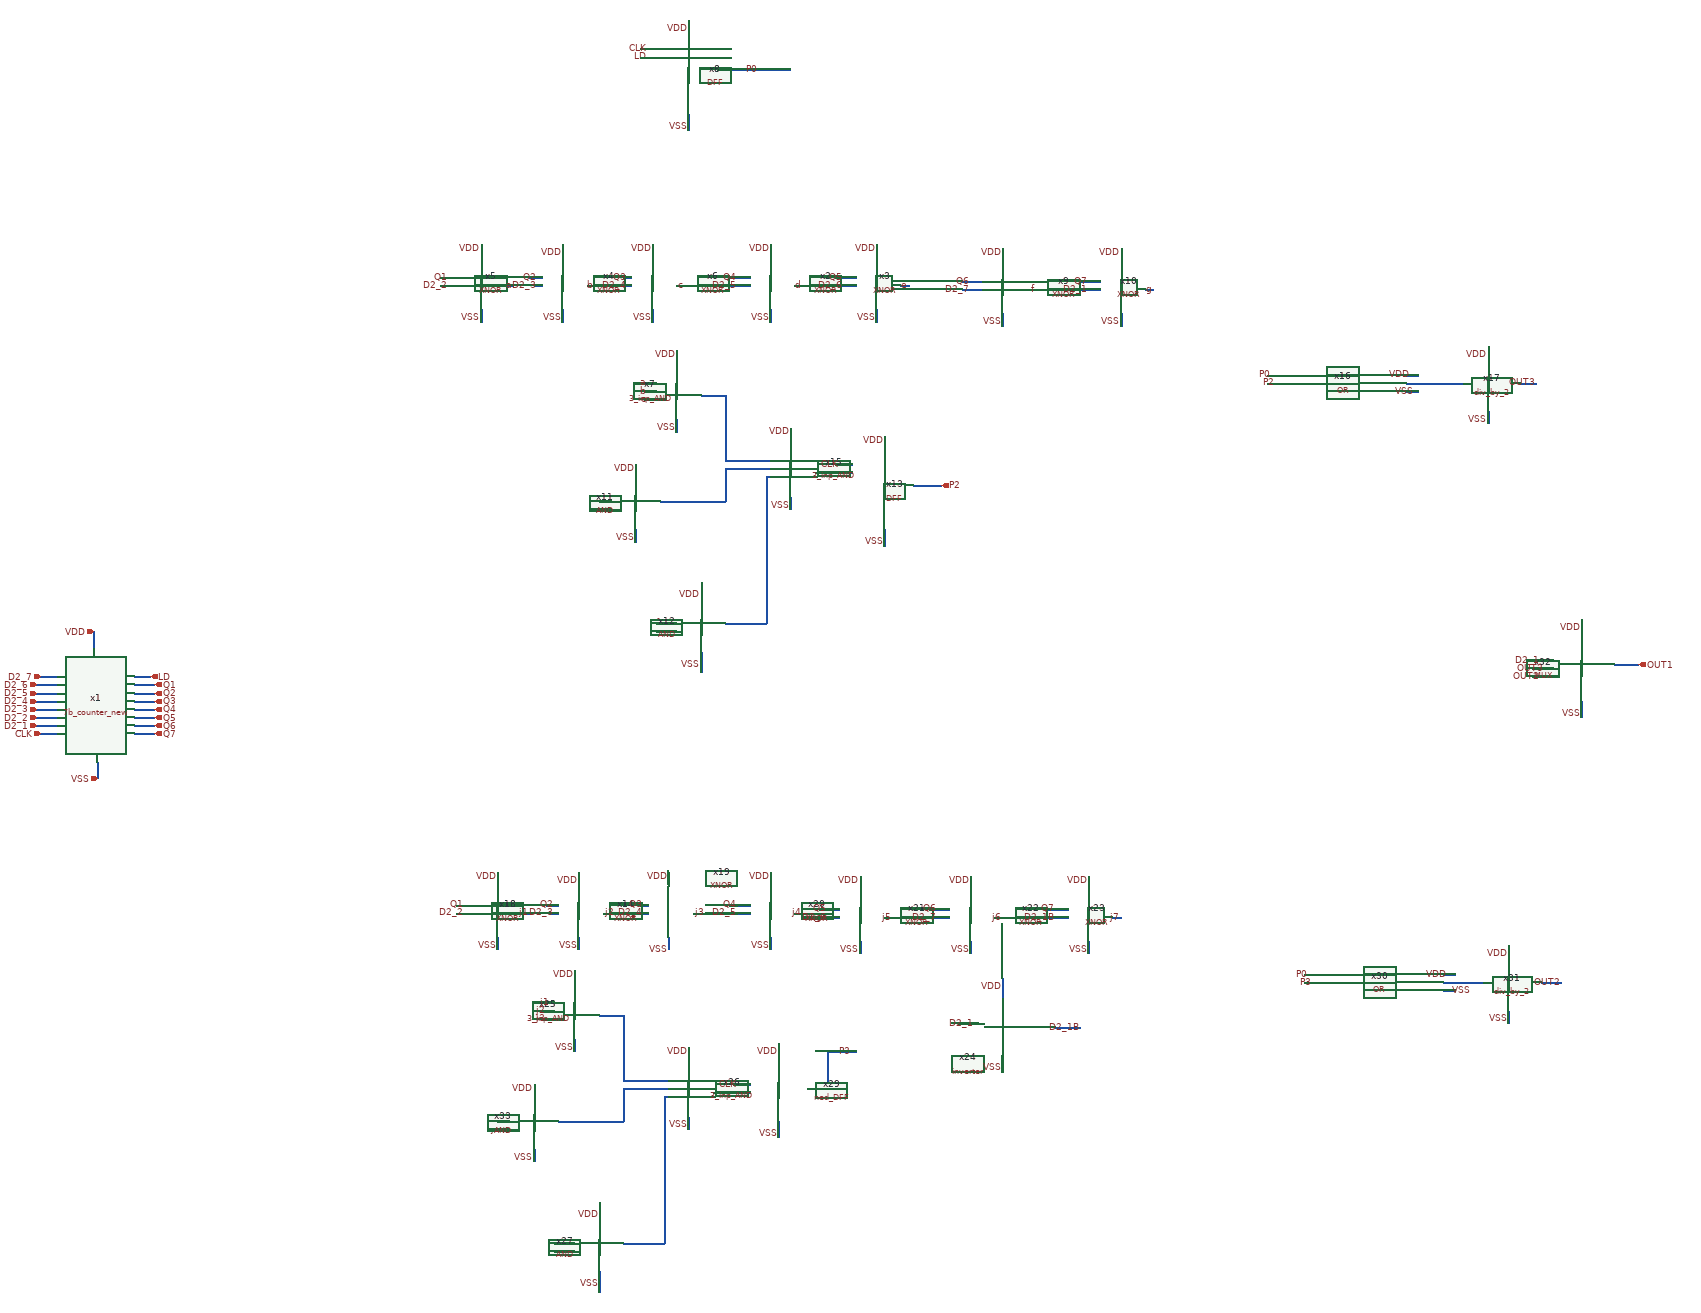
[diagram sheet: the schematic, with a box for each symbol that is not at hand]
v {xschem version=3.4.8RC file_version=1.3}
G {}
K {}
V {}
S {}
F {}
E {}
N 550 -1620 550 -1580 {
lab=VDD}
N 560 -1300 560 -1260 {
lab=VSS}
N 420 -1370 460 -1370 {
lab=CLK}
N 650 -1510 690 -1510 {
lab=LD}
N 410 -1390 460 -1390 {
lab=D2_1}
N 410 -1430 460 -1430 {
lab=D2_3}
N 410 -1410 460 -1410 {
lab=D2_2}
N 410 -1450 460 -1450 {
lab=D2_4}
N 410 -1470 460 -1470 {
lab=D2_5}
N 410 -1490 460 -1490 {
lab=D2_6}
N 420 -1510 460 -1510 {
lab=D2_7}
N 650 -1490 700 -1490 {
lab=Q1}
N 650 -1470 700 -1470 {
lab=Q2}
N 650 -1450 700 -1450 {
lab=Q3}
N 650 -1430 700 -1430 {
lab=Q4}
N 650 -1410 700 -1410 {
lab=Q5}
N 650 -1390 700 -1390 {
lab=Q6}
N 650 -1370 700 -1370 {
lab=Q7}
N 1400 -2490 1450 -2490 {
lab=Q1}
N 1400 -2470 1450 -2470 {
lab=D2_2}
N 1620 -2490 1650 -2490 {
lab=Q2}
N 1630 -2470 1650 -2470 {
lab=D2_3}
N 1850 -2490 1870 -2490 {
lab=Q3}
N 1850 -2470 1870 -2470 {
lab=D2_4}
N 1760 -2470 1790 -2470 {
lab=b}
N 1500 -2570 1500 -2540 {
lab=VDD}
N 1500 -2410 1500 -2380 {
lab=VSS}
N 1700 -2570 1700 -2540 {
lab=VDD}
N 1700 -2410 1700 -2380 {
lab=VSS}
N 1920 -2570 1920 -2540 {
lab=VDD}
N 1920 -2410 1920 -2380 {
lab=VSS}
N 1980 -2470 2010 -2470 {
lab=c}
N 1560 -2470 1580 -2470 {
lab=a}
N 1900 -2230 1930 -2230 {
lab=a}
N 1900 -2210 1930 -2210 {
lab=b}
N 1900 -2190 1930 -2190 {
lab=c}
N 1980 -2310 1980 -2280 {
lab=VDD}
N 2560 -1980 2630 -1980 {
lab=P2}
N 2110 -2490 2160 -2490 {
lab=Q4}
N 2110 -2470 2160 -2470 {
lab=D2_5}
N 2210 -2570 2210 -2540 {
lab=VDD}
N 2210 -2410 2210 -2380 {
lab=VSS}
N 2270 -2470 2290 -2470 {
lab=d}
N 2370 -2490 2420 -2490 {
lab=Q5}
N 2370 -2470 2420 -2470 {
lab=D2_6}
N 2470 -2570 2470 -2540 {
lab=VDD}
N 2470 -2410 2470 -2380 {
lab=VSS}
N 2530 -2470 2550 -2470 {
lab=e}
N 2680 -2480 2730 -2480 {
lab=Q6}
N 2680 -2460 2730 -2460 {
lab=D2_7}
N 2780 -2560 2780 -2530 {
lab=VDD}
N 2780 -2400 2780 -2370 {
lab=VSS}
N 2840 -2460 2860 -2460 {
lab=f}
N 2970 -2480 3020 -2480 {
lab=Q7}
N 2970 -2460 3020 -2460 {
lab=D2_1}
N 3070 -2560 3070 -2530 {
lab=VDD}
N 3070 -2400 3070 -2370 {
lab=VSS}
N 3130 -2460 3150 -2460 {
lab=g}
N 1980 -2140 1980 -2110 {
lab=VSS}
N 1790 -1940 1820 -1940 {
lab=d}
N 1790 -1920 1820 -1920 {
lab=e}
N 1880 -2030 1880 -2000 {
lab=VDD}
N 1880 -1870 1880 -1840 {
lab=VSS}
N 2040 -1740 2040 -1700 {
lab=VDD}
N 2040 -1570 2040 -1520 {
lab=VSS}
N 1930 -1640 1980 -1640 {
lab=f}
N 1930 -1620 1980 -1620 {
lab=g}
N 2180 -2040 2210 -2040 {
lab=#net1}
N 2180 -2020 2210 -2020 {
lab=#net2}
N 2260 -2120 2260 -2090 {
lab=VDD}
N 2260 -1950 2260 -1920 {
lab=VSS}
N 2040 -2200 2100 -2200 {
lab=#net1}
N 2100 -2200 2100 -2040 {
lab=#net1}
N 2100 -2040 2180 -2040 {
lab=#net1}
N 2030 -1940 2100 -1940 {
lab=#net2}
N 2100 -2020 2100 -1960 {
lab=#net2}
N 2100 -2020 2180 -2020 {
lab=#net2}
N 2200 -2000 2210 -2000 {
lab=#net3}
N 2320 -2010 2380 -2010 {
lab=#net4}
N 3430 -2250 3470 -2250 {
lab=P0}
N 3430 -2230 3470 -2230 {
lab=P2}
N 3770 -2250 3800 -2250 {
lab=VDD}
N 3770 -2210 3800 -2210 {
lab=VSS}
N 3860 -2230 3910 -2230 {
lab=#net5}
N 3970 -2320 3970 -2290 {
lab=VDD}
N 3970 -2160 3970 -2130 {
lab=VSS}
N 4050 -2230 4090 -2230 {
lab=OUT3}
N 2200 -2000 2200 -1660 {
lab=#net3}
N 1940 -1940 2030 -1940 {
lab=#net2}
N 2100 -1640 2200 -1640 {
lab=#net3}
N 2010 -3120 2010 -3080 {
lab=VDD}
N 2010 -2890 2010 -2850 {
lab=VSS}
N 1890 -3050 1930 -3050 {
lab=CLK}
N 1890 -3030 1930 -3030 {
lab=LD}
N 2080 -3000 2120 -3000 {
lab=P0}
N 2490 -2100 2490 -2060 {
lab=VDD}
N 2490 -1870 2490 -1830 {
lab=VSS}
N 2370 -2030 2410 -2030 {
lab=CLK}
N 2380 -2010 2410 -2010 {
lab=#net4}
N 1440 -950 1490 -950 {
lab=Q1}
N 1440 -930 1490 -930 {
lab=D2_2}
N 1660 -950 1690 -950 {
lab=Q2}
N 1670 -930 1690 -930 {
lab=D2_3}
N 1890 -950 1910 -950 {
lab=Q3}
N 1890 -930 1910 -930 {
lab=D2_4}
N 1800 -930 1830 -930 {
lab=j2}
N 1540 -1030 1540 -1000 {
lab=VDD}
N 1540 -870 1540 -840 {
lab=VSS}
N 1740 -1030 1740 -1000 {
lab=VDD}
N 1740 -870 1740 -840 {
lab=VSS}
N 1960 -1030 1960 -1000 {
lab=VDD}
N 1960 -870 1960 -840 {
lab=VSS}
N 2020 -930 2050 -930 {
lab=j3}
N 1600 -930 1620 -930 {
lab=j1}
N 2110 -950 2160 -950 {
lab=Q4}
N 2110 -930 2160 -930 {
lab=D2_5}
N 2210 -1030 2210 -1000 {
lab=VDD}
N 2210 -870 2210 -840 {
lab=VSS}
N 2270 -930 2290 -930 {
lab=j4}
N 2330 -940 2380 -940 {
lab=Q5}
N 2330 -920 2380 -920 {
lab=D2_6}
N 2430 -1020 2430 -990 {
lab=VDD}
N 2430 -860 2430 -830 {
lab=VSS}
N 2490 -920 2510 -920 {
lab=j5}
N 2600 -940 2650 -940 {
lab=Q6}
N 2600 -920 2650 -920 {
lab=D2_7}
N 2700 -1020 2700 -990 {
lab=VDD}
N 2700 -860 2700 -830 {
lab=VSS}
N 2760 -920 2780 -920 {
lab=j6}
N 2890 -940 2940 -940 {
lab=Q7}
N 2890 -920 2940 -920 {
lab=D2_1B}
N 2990 -1020 2990 -990 {
lab=VDD}
N 2990 -860 2990 -830 {
lab=VSS}
N 3050 -920 3070 -920 {
lab=j7}
N 2910 -650 2970 -650 {
lab=D2_1B}
N 2670 -660 2720 -660 {
lab=D2_1}
N 2780 -770 2780 -720 {
lab=VDD}
N 2780 -580 2780 -540 {
lab=VSS}
N 1650 -710 1680 -710 {
lab=j1}
N 1650 -690 1680 -690 {
lab=j2}
N 1650 -670 1680 -670 {
lab=j3}
N 1730 -790 1730 -760 {
lab=VDD}
N 2350 -590 2420 -590 {
lab=P3}
N 1730 -620 1730 -590 {
lab=VSS}
N 1540 -420 1570 -420 {
lab=j4}
N 1540 -400 1570 -400 {
lab=j5}
N 1630 -510 1630 -480 {
lab=VDD}
N 1630 -350 1630 -320 {
lab=VSS}
N 1790 -220 1790 -180 {
lab=VDD}
N 1790 -50 1790 0 {
lab=VSS}
N 1680 -120 1730 -120 {
lab=j6}
N 1680 -100 1730 -100 {
lab=j7}
N 1930 -520 1960 -520 {
lab=#net6}
N 1930 -500 1960 -500 {
lab=#net7}
N 2010 -600 2010 -570 {
lab=VDD}
N 2010 -430 2010 -400 {
lab=VSS}
N 1790 -680 1850 -680 {
lab=#net6}
N 1850 -680 1850 -520 {
lab=#net6}
N 1850 -520 1930 -520 {
lab=#net6}
N 1780 -420 1850 -420 {
lab=#net7}
N 1850 -500 1850 -440 {
lab=#net7}
N 1850 -500 1930 -500 {
lab=#net7}
N 1950 -480 1960 -480 {
lab=#net8}
N 2070 -490 2130 -490 {
lab=#net9}
N 1950 -480 1950 -140 {
lab=#net8}
N 1690 -420 1780 -420 {
lab=#net7}
N 1850 -120 1950 -120 {
lab=#net8}
N 2350 -570 2350 -510 {
lab=P3}
N 2230 -610 2230 -570 {
lab=VDD}
N 2230 -420 2230 -380 {
lab=VSS}
N 2120 -510 2160 -510 {
lab=CLK}
N 2300 -500 2340 -500 {
lab=P3}
N 2130 -490 2160 -490 {
lab=#net9}
N 2340 -500 2350 -500 {
lab=P3}
N 2350 -510 2350 -500 {
lab=P3}
N 2350 -590 2350 -570 {
lab=P3}
N 3520 -780 3560 -780 {
lab=P0}
N 3520 -760 3560 -760 {
lab=P3}
N 3860 -780 3890 -780 {
lab=VDD}
N 4020 -690 4020 -660 {
lab=VSS}
N 4100 -760 4150 -760 {
lab=OUT2}
N 4020 -850 4020 -820 {
lab=VDD}
N 3860 -740 3890 -740 {
lab=VSS}
N 3860 -760 3900 -760 {
lab=#net10}
N 4200 -1650 4200 -1610 {
lab=VDD}
N 4200 -1450 4200 -1410 {
lab=VSS}
N 4080 -1550 4130 -1550 {
lab=D2_1}
N 4080 -1530 4130 -1530 {
lab=OUT3}
N 4080 -1510 4130 -1510 {
lab=OUT2}
N 4280 -1540 4340 -1540 {
lab=OUT1}
N 2120 -3000 2170 -3000 {
lab=P0}
N 2220 -3000 2260 -3000 {
lab=P0}
N 2170 -3000 2220 -3000 {
lab=P0}
N 3900 -760 3960 -760 {
lab=#net10}
N 3770 -2230 3860 -2230 {
lab=#net5}
N 2100 -1960 2100 -1940 {lab=#net2}
N 2200 -1660 2200 -1640 {lab=#net3}
N 1850 -440 1850 -420 {lab=#net7}
N 1950 -140 1950 -120 {lab=#net8}
C {devices/iopin.sym} 550 -1620 3 0 {name=p1 lab=VDD}
C {devices/iopin.sym} 560 -1260 1 0 {name=p2 lab=VSS}
C {devices/ipin.sym} 410 -1390 0 0 {name=p3 lab=D2_1}
C {devices/ipin.sym} 420 -1370 0 0 {name=p4 lab=CLK}
C {devices/ipin.sym} 410 -1410 0 0 {name=p5 lab=D2_2}
C {devices/ipin.sym} 410 -1430 0 0 {name=p6 lab=D2_3}
C {devices/ipin.sym} 410 -1450 0 0 {name=p7 lab=D2_4}
C {devices/ipin.sym} 410 -1470 0 0 {name=p8 lab=D2_5}
C {devices/ipin.sym} 410 -1490 0 0 {name=p9 lab=D2_6}
C {devices/ipin.sym} 420 -1510 0 0 {name=p10 lab=D2_7}
C {devices/opin.sym} 690 -1510 0 0 {name=p12 lab=LD}
C {devices/opin.sym} 700 -1490 0 0 {name=p13 lab=Q1}
C {devices/opin.sym} 700 -1470 0 0 {name=p14 lab=Q2}
C {devices/opin.sym} 700 -1450 0 0 {name=p15 lab=Q3}
C {devices/opin.sym} 700 -1430 0 0 {name=p16 lab=Q4}
C {devices/opin.sym} 700 -1410 0 0 {name=p17 lab=Q5}
C {devices/opin.sym} 700 -1390 0 0 {name=p18 lab=Q6}
C {devices/opin.sym} 700 -1370 0 0 {name=p19 lab=Q7}
C {XNOR.sym} 1800 -2470 0 0 {name=x4}
C {XNOR.sym} 1600 -2470 0 0 {name=x5}
C {XNOR.sym} 2020 -2470 0 0 {name=x6}
C {devices/lab_wire.sym} 1500 -2560 0 0 {name=p21 sig_type=std_logic lab=VDD}
C {devices/lab_wire.sym} 1700 -2550 0 0 {name=p22 sig_type=std_logic lab=VDD}
C {devices/lab_wire.sym} 1920 -2560 0 0 {name=p23 sig_type=std_logic lab=VDD}
C {devices/lab_wire.sym} 1500 -2390 0 0 {name=p24 sig_type=std_logic lab=VSS}
C {devices/lab_wire.sym} 1700 -2390 0 0 {name=p25 sig_type=std_logic lab=VSS}
C {devices/lab_wire.sym} 1980 -2120 0 0 {name=p26 sig_type=std_logic lab=VSS}
C {devices/lab_wire.sym} 1420 -2490 0 0 {name=p27 sig_type=std_logic lab=Q1}
C {devices/lab_wire.sym} 1640 -2490 0 0 {name=p28 sig_type=std_logic lab=Q2}
C {devices/lab_wire.sym} 1860 -2490 0 0 {name=p29 sig_type=std_logic lab=Q3}
C {devices/lab_wire.sym} 1860 -2470 0 0 {name=p30 sig_type=std_logic lab=D2_4}
C {devices/lab_wire.sym} 1640 -2470 0 0 {name=p31 sig_type=std_logic lab=D2_3}
C {devices/lab_wire.sym} 1420 -2470 0 0 {name=p32 sig_type=std_logic lab=D2_2}
C {3_inp_AND.sym} 2080 -2210 0 0 {name=x7}
C {devices/lab_wire.sym} 1980 -2300 0 0 {name=p33 sig_type=std_logic lab=VDD}
C {devices/lab_wire.sym} 1580 -2470 0 0 {name=p35 sig_type=std_logic lab=a}
C {devices/lab_wire.sym} 1780 -2470 0 0 {name=p36 sig_type=std_logic lab=b}
C {devices/lab_wire.sym} 2000 -2470 0 0 {name=p37 sig_type=std_logic lab=c}
C {devices/lab_wire.sym} 1910 -2230 0 0 {name=p38 sig_type=std_logic lab=a}
C {devices/opin.sym} 2630 -1980 0 0 {name=p43 lab=P2}
C {XNOR.sym} 2310 -2470 0 0 {name=x2}
C {devices/lab_wire.sym} 2210 -2560 0 0 {name=p45 sig_type=std_logic lab=VDD}
C {devices/lab_wire.sym} 2210 -2390 0 0 {name=p46 sig_type=std_logic lab=VSS}
C {devices/lab_wire.sym} 2130 -2490 0 0 {name=p47 sig_type=std_logic lab=Q4}
C {devices/lab_wire.sym} 2130 -2470 0 0 {name=p48 sig_type=std_logic lab=D2_5}
C {devices/lab_wire.sym} 2290 -2470 0 0 {name=p49 sig_type=std_logic lab=d}
C {XNOR.sym} 2570 -2470 0 0 {name=x3}
C {devices/lab_wire.sym} 2470 -2560 0 0 {name=p50 sig_type=std_logic lab=VDD}
C {devices/lab_wire.sym} 2470 -2390 0 0 {name=p51 sig_type=std_logic lab=VSS}
C {devices/lab_wire.sym} 2390 -2490 0 0 {name=p52 sig_type=std_logic lab=Q5}
C {devices/lab_wire.sym} 2390 -2470 0 0 {name=p53 sig_type=std_logic lab=D2_6}
C {devices/lab_wire.sym} 2550 -2470 0 0 {name=p54 sig_type=std_logic lab=e}
C {XNOR.sym} 2880 -2460 0 0 {name=x9}
C {devices/lab_wire.sym} 2780 -2550 0 0 {name=p55 sig_type=std_logic lab=VDD}
C {devices/lab_wire.sym} 2780 -2380 0 0 {name=p56 sig_type=std_logic lab=VSS}
C {devices/lab_wire.sym} 2700 -2480 0 0 {name=p57 sig_type=std_logic lab=Q6}
C {devices/lab_wire.sym} 2700 -2460 0 0 {name=p58 sig_type=std_logic lab=D2_7}
C {devices/lab_wire.sym} 2860 -2460 0 0 {name=p59 sig_type=std_logic lab=f}
C {XNOR.sym} 3170 -2460 0 0 {name=x10}
C {devices/lab_wire.sym} 3070 -2550 0 0 {name=p60 sig_type=std_logic lab=VDD}
C {devices/lab_wire.sym} 3070 -2380 0 0 {name=p61 sig_type=std_logic lab=VSS}
C {devices/lab_wire.sym} 2990 -2480 0 0 {name=p62 sig_type=std_logic lab=Q7}
C {devices/lab_wire.sym} 3150 -2460 0 0 {name=p64 sig_type=std_logic lab=g}
C {devices/lab_wire.sym} 1880 -1850 0 0 {name=p34 sig_type=std_logic lab=VSS}
C {devices/lab_wire.sym} 1880 -2020 0 0 {name=p70 sig_type=std_logic lab=VDD}
C {devices/lab_wire.sym} 1800 -1940 0 0 {name=p71 sig_type=std_logic lab=d}
C {devices/lab_wire.sym} 1800 -1920 0 0 {name=p72 sig_type=std_logic lab=e}
C {devices/lab_wire.sym} 1940 -1640 0 0 {name=p75 sig_type=std_logic lab=f}
C {devices/lab_wire.sym} 2040 -1710 0 0 {name=p76 sig_type=std_logic lab=VDD}
C {devices/lab_wire.sym} 2040 -1540 0 0 {name=p77 sig_type=std_logic lab=VSS}
C {devices/lab_wire.sym} 2260 -1930 0 0 {name=p80 sig_type=std_logic lab=VSS}
C {3_inp_AND.sym} 2360 -2020 0 0 {name=x15}
C {devices/lab_wire.sym} 2260 -2110 0 0 {name=p81 sig_type=std_logic lab=VDD}
C {OR.sym} 3620 -2230 0 0 {name=x16}
C {devices/lab_wire.sym} 3780 -2250 1 0 {name=p84 sig_type=std_logic lab=VDD}
C {devices/lab_wire.sym} 3790 -2210 3 0 {name=p85 sig_type=std_logic lab=VSS}
C {div_by_2.sym} 4060 -2210 0 0 {name=x17}
C {devices/lab_wire.sym} 3970 -2300 0 0 {name=p86 sig_type=std_logic lab=VDD}
C {devices/lab_wire.sym} 3970 -2140 0 0 {name=p87 sig_type=std_logic lab=VSS}
C {devices/lab_wire.sym} 1910 -2210 0 0 {name=p94 sig_type=std_logic lab=b}
C {devices/lab_wire.sym} 1910 -2190 0 0 {name=p95 sig_type=std_logic lab=c}
C {devices/lab_wire.sym} 1940 -1620 0 0 {name=p39 sig_type=std_logic lab=g}
C {7b_counter_new.sym} 610 -1420 0 0 {name=x1}
C {devices/lab_wire.sym} 2990 -2460 0 0 {name=p11 sig_type=std_logic lab=D2_1}
C {devices/lab_wire.sym} 1910 -3030 0 0 {name=p20 sig_type=std_logic lab=LD}
C {DFF.sym} 2080 -3030 0 0 {name=x8}
C {devices/lab_wire.sym} 2010 -3100 0 0 {name=p40 sig_type=std_logic lab=VDD}
C {devices/lab_wire.sym} 2010 -2860 0 0 {name=p41 sig_type=std_logic lab=VSS}
C {devices/lab_wire.sym} 1910 -3050 0 0 {name=p42 sig_type=std_logic lab=CLK}
C {devices/lab_wire.sym} 3440 -2250 0 0 {name=p63 sig_type=std_logic lab=P0}
C {devices/lab_wire.sym} 2490 -2090 0 0 {name=p66 sig_type=std_logic lab=VDD}
C {devices/lab_wire.sym} 2490 -1840 0 0 {name=p67 sig_type=std_logic lab=VSS}
C {devices/lab_wire.sym} 2380 -2030 0 0 {name=p65 sig_type=std_logic lab=CLK}
C {XNOR.sym} 1840 -930 0 0 {name=x14}
C {XNOR.sym} 1640 -930 0 0 {name=x18}
C {XNOR.sym} 2060 -930 0 0 {name=x19}
C {devices/lab_wire.sym} 1540 -1020 0 0 {name=p68 sig_type=std_logic lab=VDD}
C {devices/lab_wire.sym} 1740 -1010 0 0 {name=p73 sig_type=std_logic lab=VDD}
C {devices/lab_wire.sym} 1960 -1020 0 0 {name=p74 sig_type=std_logic lab=VDD}
C {devices/lab_wire.sym} 1540 -850 0 0 {name=p78 sig_type=std_logic lab=VSS}
C {devices/lab_wire.sym} 1740 -850 0 0 {name=p79 sig_type=std_logic lab=VSS}
C {devices/lab_wire.sym} 1460 -950 0 0 {name=p82 sig_type=std_logic lab=Q1}
C {devices/lab_wire.sym} 1680 -950 0 0 {name=p89 sig_type=std_logic lab=Q2}
C {devices/lab_wire.sym} 1900 -950 0 0 {name=p90 sig_type=std_logic lab=Q3}
C {devices/lab_wire.sym} 1900 -930 0 0 {name=p91 sig_type=std_logic lab=D2_4}
C {devices/lab_wire.sym} 1680 -930 0 0 {name=p92 sig_type=std_logic lab=D2_3}
C {devices/lab_wire.sym} 1460 -930 0 0 {name=p93 sig_type=std_logic lab=D2_2}
C {devices/lab_wire.sym} 1620 -930 0 0 {name=p96 sig_type=std_logic lab=j1}
C {XNOR.sym} 2310 -930 0 0 {name=x20}
C {devices/lab_wire.sym} 2210 -1020 0 0 {name=p99 sig_type=std_logic lab=VDD}
C {devices/lab_wire.sym} 2210 -850 0 0 {name=p100 sig_type=std_logic lab=VSS}
C {devices/lab_wire.sym} 2130 -950 0 0 {name=p101 sig_type=std_logic lab=Q4}
C {devices/lab_wire.sym} 2130 -930 0 0 {name=p102 sig_type=std_logic lab=D2_5}
C {XNOR.sym} 2530 -920 0 0 {name=x21}
C {devices/lab_wire.sym} 2430 -1010 0 0 {name=p104 sig_type=std_logic lab=VDD}
C {devices/lab_wire.sym} 2430 -840 0 0 {name=p105 sig_type=std_logic lab=VSS}
C {devices/lab_wire.sym} 2350 -940 0 0 {name=p106 sig_type=std_logic lab=Q5}
C {devices/lab_wire.sym} 2350 -920 0 0 {name=p107 sig_type=std_logic lab=D2_6}
C {XNOR.sym} 2800 -920 0 0 {name=x22}
C {devices/lab_wire.sym} 2700 -1010 0 0 {name=p109 sig_type=std_logic lab=VDD}
C {devices/lab_wire.sym} 2700 -840 0 0 {name=p110 sig_type=std_logic lab=VSS}
C {devices/lab_wire.sym} 2620 -940 0 0 {name=p111 sig_type=std_logic lab=Q6}
C {devices/lab_wire.sym} 2620 -920 0 0 {name=p112 sig_type=std_logic lab=D2_7}
C {XNOR.sym} 3090 -920 0 0 {name=x23}
C {devices/lab_wire.sym} 2990 -1010 0 0 {name=p114 sig_type=std_logic lab=VDD}
C {devices/lab_wire.sym} 2990 -840 0 0 {name=p115 sig_type=std_logic lab=VSS}
C {devices/lab_wire.sym} 2910 -940 0 0 {name=p116 sig_type=std_logic lab=Q7}
C {devices/lab_wire.sym} 2910 -920 0 0 {name=p118 sig_type=std_logic lab=D2_1B}
C {inverter.sym} 2870 -640 0 0 {name=x24}
C {devices/lab_wire.sym} 2780 -750 0 0 {name=p119 sig_type=std_logic lab=VDD}
C {devices/lab_wire.sym} 2780 -550 0 0 {name=p120 sig_type=std_logic lab=VSS}
C {devices/lab_wire.sym} 2710 -660 0 0 {name=p121 sig_type=std_logic lab=D2_1}
C {devices/lab_wire.sym} 2970 -650 0 0 {name=p122 sig_type=std_logic lab=D2_1B}
C {devices/lab_wire.sym} 1830 -930 0 0 {name=p97 sig_type=std_logic lab=j2}
C {devices/lab_wire.sym} 2050 -930 0 0 {name=p98 sig_type=std_logic lab=j3}
C {devices/lab_wire.sym} 2290 -930 0 0 {name=p103 sig_type=std_logic lab=j4}
C {devices/lab_wire.sym} 2510 -920 0 0 {name=p108 sig_type=std_logic lab=j5}
C {devices/lab_wire.sym} 2780 -920 0 0 {name=p113 sig_type=std_logic lab=j6}
C {devices/lab_wire.sym} 3070 -920 0 0 {name=p117 sig_type=std_logic lab=j7}
C {devices/lab_wire.sym} 1730 -600 0 0 {name=p123 sig_type=std_logic lab=VSS}
C {3_inp_AND.sym} 1830 -690 0 0 {name=x25}
C {devices/lab_wire.sym} 1730 -780 0 0 {name=p124 sig_type=std_logic lab=VDD}
C {devices/lab_wire.sym} 1630 -330 0 0 {name=p127 sig_type=std_logic lab=VSS}
C {devices/lab_wire.sym} 1630 -500 0 0 {name=p128 sig_type=std_logic lab=VDD}
C {devices/lab_wire.sym} 1790 -190 0 0 {name=p132 sig_type=std_logic lab=VDD}
C {devices/lab_wire.sym} 1790 -20 0 0 {name=p133 sig_type=std_logic lab=VSS}
C {devices/lab_wire.sym} 2010 -410 0 0 {name=p134 sig_type=std_logic lab=VSS}
C {3_inp_AND.sym} 2110 -500 0 0 {name=x26}
C {devices/lab_wire.sym} 2010 -590 0 0 {name=p135 sig_type=std_logic lab=VDD}
C {devices/lab_wire.sym} 2230 -590 0 0 {name=p139 sig_type=std_logic lab=VDD}
C {devices/lab_wire.sym} 2230 -390 0 0 {name=p140 sig_type=std_logic lab=VSS}
C {devices/lab_wire.sym} 2410 -590 0 0 {name=p141 sig_type=std_logic lab=P3}
C {devices/lab_wire.sym} 2130 -510 0 0 {name=p142 sig_type=std_logic lab=CLK}
C {devices/lab_wire.sym} 1670 -710 0 0 {name=p125 sig_type=std_logic lab=j1}
C {devices/lab_wire.sym} 1660 -690 0 0 {name=p129 sig_type=std_logic lab=j2}
C {devices/lab_wire.sym} 1660 -670 0 0 {name=p130 sig_type=std_logic lab=j3}
C {devices/lab_wire.sym} 1550 -420 0 0 {name=p131 sig_type=std_logic lab=j4}
C {devices/lab_wire.sym} 1550 -400 0 0 {name=p136 sig_type=std_logic lab=j5}
C {devices/lab_wire.sym} 1700 -120 0 0 {name=p137 sig_type=std_logic lab=j6}
C {devices/lab_wire.sym} 1700 -100 0 0 {name=p138 sig_type=std_logic lab=j7}
C {ned_DFF.sym} 2310 -490 0 0 {name=x29}
C {OR.sym} 3710 -760 0 0 {name=x30}
C {devices/lab_wire.sym} 3540 -760 0 0 {name=p88 sig_type=std_logic lab=P3}
C {devices/lab_wire.sym} 3870 -780 1 0 {name=p126 sig_type=std_logic lab=VDD}
C {devices/lab_wire.sym} 4020 -670 0 0 {name=p143 sig_type=std_logic lab=VSS}
C {div_by_2.sym} 4110 -740 0 0 {name=x31}
C {devices/lab_wire.sym} 4020 -830 0 0 {name=p144 sig_type=std_logic lab=VDD}
C {devices/lab_wire.sym} 3880 -740 2 0 {name=p145 sig_type=std_logic lab=VSS}
C {devices/lab_wire.sym} 3530 -780 0 0 {name=p146 sig_type=std_logic lab=P0}
C {devices/lab_wire.sym} 4150 -760 0 0 {name=p147 sig_type=std_logic lab=OUT2}
C {devices/opin.sym} 4340 -1540 0 0 {name=p69 lab=OUT1}
C {devices/lab_wire.sym} 1960 -840 0 0 {name=p148 sig_type=std_logic lab=VSS}
C {MUX.sym} 4280 -1530 0 0 {name=x32}
C {devices/lab_wire.sym} 4100 -1550 0 0 {name=p149 sig_type=std_logic lab=D2_1}
C {devices/lab_wire.sym} 4090 -2230 0 0 {name=p150 sig_type=std_logic lab=OUT3}
C {devices/lab_wire.sym} 4110 -1530 0 0 {name=p151 sig_type=std_logic lab=OUT3}
C {devices/lab_wire.sym} 4100 -1510 0 0 {name=p152 sig_type=std_logic lab=OUT2}
C {devices/lab_wire.sym} 4200 -1630 0 0 {name=p153 sig_type=std_logic lab=VDD}
C {devices/lab_wire.sym} 4200 -1420 0 0 {name=p154 sig_type=std_logic lab=VSS}
C {DFF.sym} 2560 -2010 0 0 {name=x13}
C {devices/lab_wire.sym} 2180 -3000 0 0 {name=p165 sig_type=std_logic lab=P0}
C {devices/lab_wire.sym} 3450 -2230 0 0 {name=p44 sig_type=std_logic lab=P2}
C {devices/lab_wire.sym} 1920 -2390 0 0 {name=p83 sig_type=std_logic lab=VSS}
C {AND.sym} 1720 -400 0 0 {name=x33}
C {AND.sym} 1880 -100 0 0 {name=x27}
C {AND.sym} 1970 -1920 0 0 {name=x11}
C {AND.sym} 2130 -1620 0 0 {name=x12}
